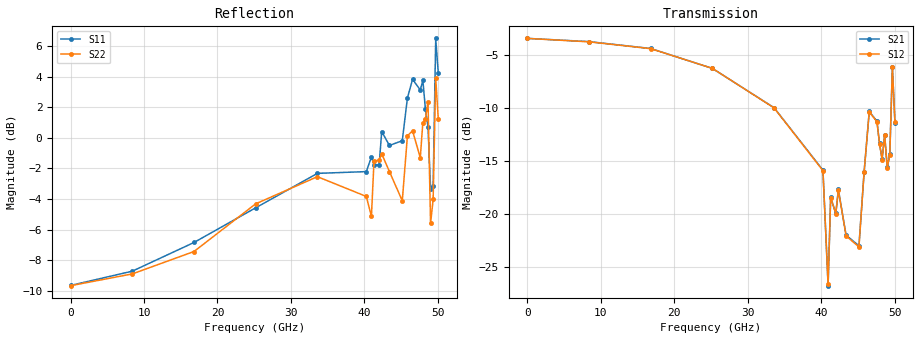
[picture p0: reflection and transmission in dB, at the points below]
! 10/31/2025 3:16:53 PM
! C:\MESURES\046-TRL-DUT-CHEP0603\DUT\DUT-2542B6-CHEP0603N-2-I.S2P
! CHANNEL.1 Sparams
! TR.MEASUREMENT
! CORRECTED.DATA
! RF.CORRECTION: CAL.A: FULL.TWO.PORT.CALCAL.A: Port 1,4
! AVERAGING.OFF
! IF.BANDWIDTH: 500HZ
! SWEEPTYPE:  FREQ.SWEEP(Linear)
! Reference Plane Port Info
! PORT:  PORT1  PORT4
! DISTANCE:  0  m  0  m
! TIME:  0  s  0  s
! PHASE.OFFSET:  0  deg.  0  deg.
! LOSS:  0  dB  0  dB
! REF.LOSS:  0  dB  0  dB
! REF.FREQ:  0  Hz  0  Hz
! Power Info
! POWER:  -10  dBm  -10  dBm
! EFF.POWER:  -10  dBm  -10  dBm
! SOURCE.ATTEN:  0  dB  0  dB
! TEST.ATTEN:  0  dB  0  dB
! PORTZ: Port1:50 Port4:50
# GHZ S RI R 50
! FREQ.GHZ  S11RE  S11IM  S41RE  S41IM  S14RE  S14IM  S44RE  S44IM
!; PortSelection: Port_14 (1-->1,4-->4)
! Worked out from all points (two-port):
!   144 points, 10 MHz to 50.05 GHz, reference 50 ohm
!   highest |S21| = -3.39 dB at 10 MHz (marker M1); lowest = -26.8 dB at 40.95 GHz (marker M2)
!   |S21| within 3 dB of the highest: start of sweep to 25.85 GHz; 49.69032 GHz to 49.72265 GHz (32.32 MHz wide, 0.065 % of centre)
!   lowest |S11| = -9.7 dB at 10 MHz (marker M3), VSWR 1.98, Z = 98.9 + j3.41 ohm
!   |S11| at or under -10 dB: nowhere
!   |S22| runs from -9.7 to 3.9 dB; largest |S21 - S12| = 0.01
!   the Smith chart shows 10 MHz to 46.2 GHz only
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0.01  0.3285 0.0154  0.6764 -0.0144  0.6761 -0.0147  0.3279 0.0151
8.4088  0.3659 -0.0145  0.6188 -0.2086  0.6175 -0.2076  0.3586 -0.00933
16.8076  0.4504 -0.0614  0.4778 -0.3724  0.4768 -0.3719  0.4243 -0.0183
25.2064  0.5649 -0.1717  0.259 -0.413  0.2581 -0.414  0.5961 -0.1214
33.6052  0.6738 -0.3626  0.0906 -0.3045  0.0898 -0.3039  0.6792 -0.3095
40.25425  0.6203 -0.4653  0.0302 -0.158  0.0291 -0.1572  0.549 -0.3349
40.95415  0.7696 -0.396  0.023 -0.0394  0.0231 -0.0401  0.5452 -0.0977
41.3041  0.748 -0.327  0.0917 -0.0767  0.0904 -0.0778  0.8358 -0.0683
42.004  0.7196 -0.3826  0.0876 -0.0491  0.0874 -0.0487  0.7518 -0.3877
42.35395  0.758 -0.7248  0.0803 -0.1026  0.0791 -0.102  0.5019 -0.7305
43.4038  0.3764 -0.866  0.034 -0.0714  0.033 -0.0712  0.3382 -0.6979
45.15355  0.6423 -0.7383  0.0615 0.0345  0.061 0.0336  0.4788 -0.3976
45.85345  1.201 -0.618  0.0552 0.1471  0.055 0.1469  0.8899 -0.4897
46.55335  1.09 -1.109  0.2593 0.1605  0.2584 0.1584  0.7392 -0.7518
47.6032  0.6442 -1.281  0.2421 -0.1286  0.2408 -0.1278  0.4439 -0.7377
47.95315  0.9776 -1.194  0.208 -0.0557  0.2069 -0.0565  0.6925 -0.8829
48.3031  0.5814 -1.097  0.1792 0.0276  0.1784 0.0273  0.731 -0.894
48.65305  0.7893 -0.7483  0.2083 0.1119  0.2079 0.1117  1.078 -0.7523
49.003  0.4532 0.5091  0.0554 -0.1561  0.0555 -0.1555  0.4041 0.3344
49.35295  0.1032 0.6862  0.1051 -0.1596  0.1047 -0.1587  0.2667 0.5698
49.7029  1.16 1.77  -0.1257 -0.4794  -0.1242 -0.4776  1.334 0.8229
50.05285  1.254 1.036  -0.0952 -0.2528  -0.097 -0.2525  1.078 0.4089
